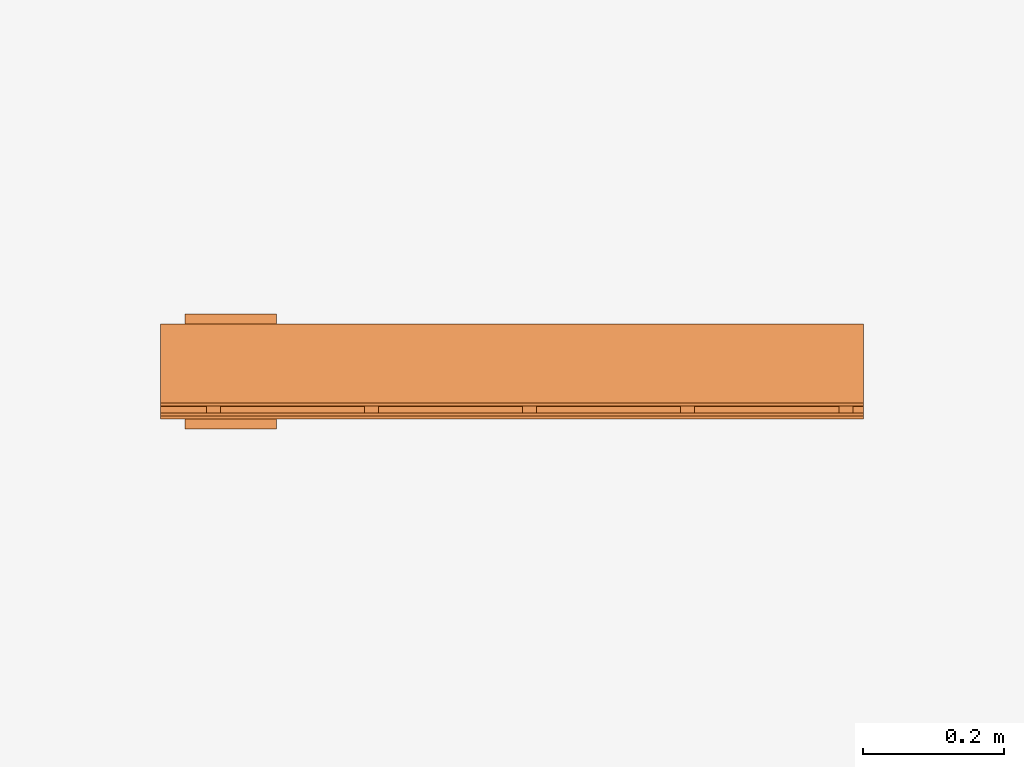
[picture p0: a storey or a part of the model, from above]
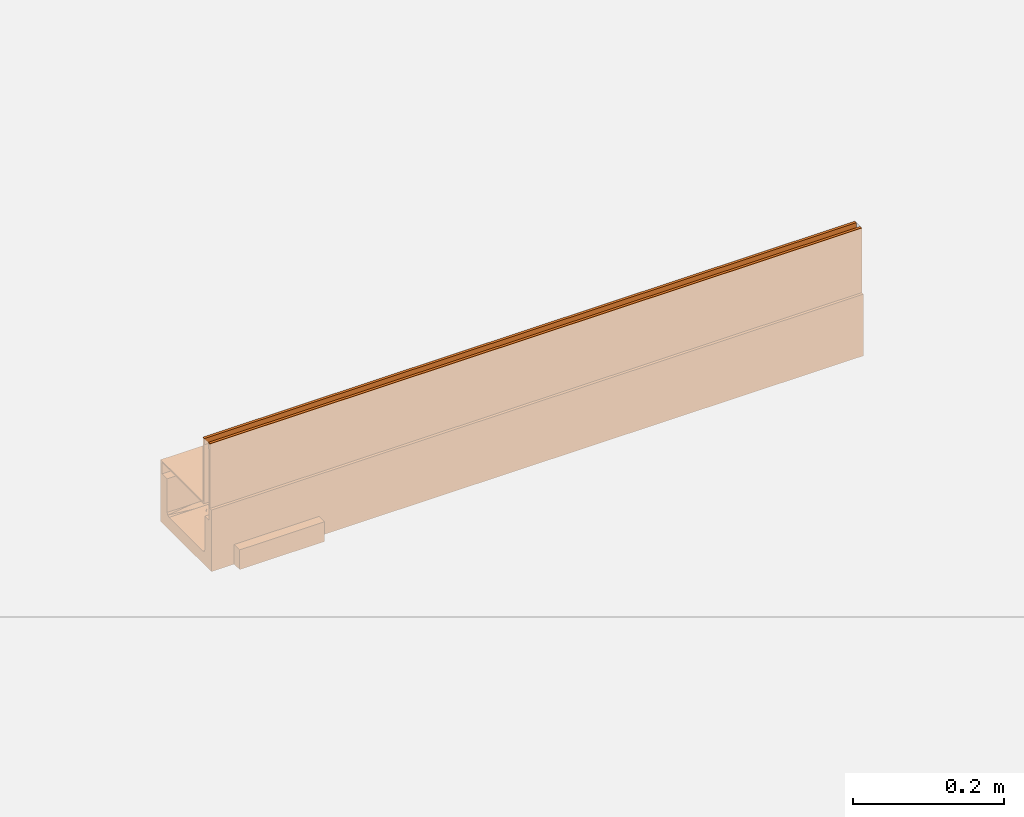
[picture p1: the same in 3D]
Properties of the parts of a building model (IFC2X3)

# File
Description: ViewDefinition [CoordinationView]
File name: 23111 - No 0100V Constant Depth Outlet Shallow Channel - 1000mm LG - Invert Depth 80mm.ifc
Time: 2013-10-31T17:33:08
Written by: Autodesk Revit 2013
Made in: 20120221_2030(x64)

# IfcProject, Project Number
LongName: Project Name; Phase: Project Status

# IfcSite, Default
RefLatitude: 42, 21, 30, 344238; RefLongitude: -71, -3, -35, -194702; RefElevation: 0 mm

# IfcBuilding
Pset_BuildingCommon - NumberOfStoreys: 1
Other - Project Address: ## Street City, State Zip; Client Name: Owner; Project Status: Project Status; Project Number: Project Number; Project Name: Project Name; Project Issue Date: Issue Date

# IfcBuildingStorey, Level 1
LongName: Level 1; Elevation: 0 mm
Constraints - Elevation Base: 0; Elevation: 0 mm
Graphics - Symbol at End 2 Default: yes; Color: 0; Line Weight: 1; Symbol at End 1 Default: no; Symbol: M_Level Head - Circle: M_Level Head - Circle; Line Pattern: Center
Dimensions - Computation Height: 0 mm
Identity Data - Building Story: yes; Name: Level 1; Structural: no

# IfcBuildingElementProxy: 23111 - No 0100V Constant Depth Outlet Shallow Channel - 1000mm LG - Invert Depth 80mm, Civil-Drainage-Channel-ACO-MultiDrain-M100D-Brickslot-Channel-System:23111 - No 0100V Constant Depth Outlet Shallow Channel - 1000mm LG - Invert Depth 80mm:23111 - No 0100V Constant Depth Outlet Shallow Channel - 1000mm LG - Invert Depth 80mm:196059
In: Level 1
Material: Steel, Galvanized, Plastic, Opaque Black, Vienite® Synthetic Resin Concrete
Dimensions - Brickslot Void Depth: 0 mm; Brickslot Access Unit Void Bottom Depth: -6605 mm; Brickslot Access Unit Void Depth: -6500 mm; Length: 1000 mm; Brickslot Void Length: 1000 mm; EndCap Position: 1000 mm; Volume: 5705980 mm3; FloorCut_Length: -1000 mm; Custom_Void_length: 0 mm; SlopingEndInvertDepth: 180 mm; InvDepth: 80 mm; EndCap_Height: 100 mm; Access_Custom_Void_Length: 0 mm; SlopingEndOverallDepth: 250 mm; GratingLength: -1000 mm; ShallowOverallDepth: 100 mm; ShallowInvDepth: 80 mm; Depth: 150 mm; Floor Cut Gap: 105 mm; Length Drain: -1000 mm; SlopingInvertDepth: 175 mm; Brickslot Access Unit Floor Cut Length: 500 mm; SlopingOverallDepth: 245 mm; FloorCut_Depth: 100 mm; FloorCut_Width: 135 mm
Construction - 23461_Load Class C250_Brickslot Grating_Galvanized Steel_500mm Long: no; 23404_Universal Endcap (Female End): no; 23466_Load Class D400_Brickslot Grating_Galvanized Steel_500mm Long: no; 23462_Load Class C250_Brickslot Access Unit_Galvanised Steel_500mm Long: no; 23460_Load Class C250_Brickslot Grating_Galvanized Steel_1000mm Long: no; 23465_Load Class D400_Brickslot Grating_Galvanized Steel_1000mm Long: yes; 23467_Load Class D400_Brickslot Access Unit_Galvanised Steel_500mm Long: no; 23404_Universal Endcap (Male End): no; 23410_Sump Unit: no; Constant Depth Channel: no; Shallow Depth Channel: no; Shallow Depth Channel with seal: yes; Constant Depth Junction Channel: no; Sloping Channel: no
Constraints - Level: Level: Level 1; Moves With Nearby Elements: no
Phasing - Phase Created: New Construction
Pset_BuildingElementProxyCommon - Reference: 23111 - No 0100V Constant Depth Outlet Shallow Channel - 1000mm LG - Invert Depth 80mm
Other - Created By: www.aco.co.uk; Revision: 1; Watermarked By: www.aco.co.uk
Materials and Finishes - Edge Rail Colour: Silver; Edge Rail Finish: Pre-galvanised; Channel Material: Vienite® Synthetic Resin Concrete; Channel Colour: Brown; Edge Rail Material: Steel
Identity Data - e-mail Sales: customersupport@aco.co.uk; Maintenance guidelines: http://www.aco.co.uk/download.php?id=173; Assembly Code: D2040; Watermark 1: This file is the property of ACO Technologies PLC; Assembly Description: Rain Water Drainage; Model: ACO MultiDrain MD Brickslot- M100D; Fax: +44 (0)1462 815895; e-mail Technical: technical@aco.co.uk; OmniClass Title: Rainwater Removal; Cost: 0; Type Comments: ACO MultiDrain M100D No 0100V Constant Depth Shallow Outlet Channel 1000mm Long; Product brochure: http://www.aco.co.uk/download.php?id=173; Installation guidelines: http://www.aco.co.uk/download.php?id=173; Price: POA - contact ACO; Manufacturer: ACO Technologies plc - ACO Water Management Division; URL: www.aco.co.uk; Telephone: +44 (0)1462 816666; Watermark 2: This file is water marked and users are prohibited to reproduce, adapt, distribute this information; Address: ACO Business Park, Hitchin Road, Shefford, Bedfordshire, United Kingdom SG17 5TE; Watermarked With: BIM Manager Premium Suite; Product Code: 23111; Product Page URL: http://www.aco.co.uk/product_detail.php?id=58; OmniClass Number: 23.70.50.24; Model Description: Channel drainage system
General - TagNumber: 0; SerialNumber: 0
Data - Product Dimensions: 1000mm x 135mm x 100mm (LxWxH); Channel C.S.A: 0.0059m²; Installation - Concrete Grade: Refer to brochure; Load Class: A 15 - D 400; Concrete Surround Volume - Load Class B 125 - C 250 - Concrete Pavement: 0.10m³/m; Pre-formed Outlet Ø: 110mm; Product Weight: 11 Kg; Concrete Surround Volume - Load Class A 15 - Concrete Pavement: 0.06m³/m; Hydraulic Performance: http://www.aco.co.uk/download.php?id=173; ACO Hydraulic Design Software: http://www.acodesign.co.uk; Concrete Surround Volume - Load Class D 400 - Concrete Pavement: 0.14m³/m; Product Standard: BS EN 1433:2002, CE marked; Invert Depth: 80 mm
Green Building Properties - Edge Rail Recyclable: Fully recyclable; Edge Rail Recycled Material Content: Between 40% - 90%; Channel Recycled Material Content: 20% minimum; Channel Recyclable: Fully recyclable
Model Properties - End Cap Product code 23404: No 306 Universal End Cap - 135mm wide x 300mm long - Spigot Ø110mm x 50mm long - Silver - Polypropylene - 0.16kg; Brickslot Grating Product code 23465: Load Class D400 - Brickslot Galvanised Steel - 1000mm long x 105mm high - 10mm Slot - Intake area - 10000mm²/m - 6.6 Kg; Brickslot Access Unit Product code 23462: Load Class C250 - Brickslot Access Unit Galvanised Steel - 500mm long x 105mm high - 10mm Slot - Intake area - 10000mm²/m - 6.4 Kg; Brickslot Grating Product code 23460: Load Class C250 - Brickslot Galvanised Steel - 1000mm long x 105mm high - 10mm Slot - Intake area - 10000mm²/m - 6.6 Kg; Brickslot Grating Product code 23466: Load Class D400 - Brickslot Galvanised Steel - 500mm long x 105mm high - 10mm Slot - Intake area - 10000mm²/m - 3.3 Kg; Brickslot Access Unit Product code 23467: Load Class D400 - Brickslot Access Unit Galvanised Steel - 500mm long x 105mm high - 10mm Slot - Intake area - 10000mm²/m - 6.4 Kg; Brickslot Grating Product code 23461: Load Class C250 - Brickslot Galvanised Steel - 500mm long x 105mm high - 10mm Slot - Intake area - 10000mm²/m -3.3 Kg

# IfcOpeningElement: Recess (2)
In: Level 1
Dimensions - Perimeter: 20000 mm; Area: 25000000 mm2; Volume: 24984610000 mm3; Thickness: 1000 mm
Constraints - Related to Mass: no; Room Bounding: yes; Level: Level: Level 1; Height Offset From Level: 0 mm
Phasing - Phase Created: New Construction
Structural - Structural: no; Enable Analytical Model: no
Construction - Default Thickness: 1000 mm; Function: 0
Analytical Properties - Heat Transfer Coefficient (U): 0.837; Thermal mass: 1359800; Absorptance: 0.1; Roughness: 1; Thermal Resistance (R): 1.19474
Graphics - Coarse Scale Fill Color: 0
Materials and Finishes - Structural Material: Earth

# IfcSlab: Floor:Generic Floor - 1000mm, Floor:Generic Floor - 1000mm:193825
In: Level 1
PredefinedType: FLOOR; Material: Earth 1000 mm
Dimensions - Perimeter: 20000 mm; Area: 25000000 mm2; Volume: 24984610000 mm3; Thickness: 1000 mm
Constraints - Related to Mass: no; Room Bounding: yes; Level: Level: Level 1; Height Offset From Level: 0 mm
Phasing - Phase Created: New Construction
Structural - Structural: no; Enable Analytical Model: no
Pset_SlabCommon - Reference: Generic Floor - 1000mm; IsExternal: no; LoadBearing: yes
Construction - Default Thickness: 1000 mm; Function: 0
Analytical Properties - Heat Transfer Coefficient (U): 0.837; Thermal mass: 1359800; Absorptance: 0.1; Roughness: 1; Thermal Resistance (R): 1.19474
Graphics - Coarse Scale Fill Color: 0
Materials and Finishes - Structural Material: Earth
